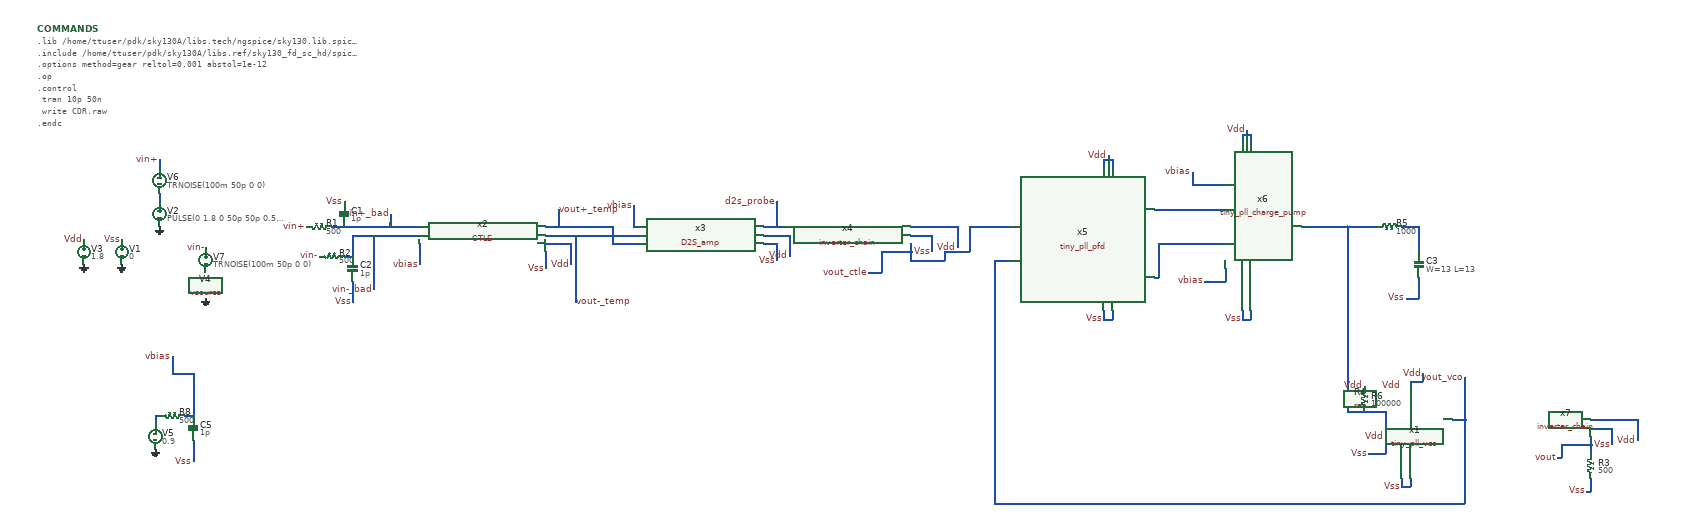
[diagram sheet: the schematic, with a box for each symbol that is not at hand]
v {xschem version=3.4.5 file_version=1.2
}
G {}
K {}
V {}
S {}
E {}
N 2080 490 2120 490 {
lab=Vss}
N 2120 470 2120 490 {
lab=Vss}
N 2030 390 2120 390 {
lab=#net1}
N 2120 390 2120 430 {
lab=#net1}
N 2180 320 2180 330 {
lab=Vdd}
N 2180 320 2210 320 {
lab=Vdd}
N 2210 300 2210 320 {
lab=Vdd}
N 2160 550 2160 570 {
lab=Vss}
N 2160 570 2180 570 {
lab=Vss}
N 2180 550 2180 570 {
lab=Vss}
N 120 -50 150 -50 {
lab=vout+_temp}
N 120 -30 150 -30 {
lab=vout-_temp}
N -390 -50 -360 -50 {
lab=vin+_bad}
N -360 -50 -290 -50 {
lab=vin+_bad}
N -360 20 -340 20 {
lab=vin-_bad}
N -290 -50 -180 -50 {
lab=vin+_bad}
N -340 80 -340 130 {
lab=Vss}
N -340 -30 -340 20 {
lab=vin-_bad}
N -340 -30 -180 -30 {
lab=vin-_bad}
N -180 -10 -180 0 {
lab=vbias}
N 120 -10 180 -10 {
lab=Vdd}
N 180 -10 180 40 {
lab=Vdd}
N 120 10 120 50 {
lab=Vss}
N -290 -30 -290 100 {
lab=vin-_bad}
N -250 -80 -250 -50 {
lab=vin+_bad}
N -800 -210 -800 -190 {
lab=vin+}
N -800 -130 -800 -110 {
lab=#net2}
N -180 0 -180 40 {
lab=vbias}
N 150 -90 150 -50 {
lab=vout+_temp}
N 190 -30 190 130 {
lab=vout-_temp}
N 150 -50 280 -50 {
lab=vout+_temp}
N -740 400 -720 400 {
lab=vbias}
N -720 460 -720 510 {
lab=Vss}
N -720 350 -720 400 {
lab=vbias}
N -720 300 -720 350 {
lab=vbias}
N -770 300 -720 300 {
lab=vbias}
N -770 260 -770 300 {
lab=vbias}
N -810 400 -800 400 {
lab=#net3}
N -810 400 -810 420 {
lab=#net3}
N 640 -50 690 -50 {
lab=d2s_probe}
N 1040 -50 1100 -50 {
lab=Vdd}
N 1100 -50 1100 0 {
lab=Vdd}
N 1040 -30 1040 10 {
lab=Vss}
N 990 -50 1040 -50 {
lab=Vdd}
N 990 -30 1040 -30 {
lab=Vss}
N 890 60 920 60 {
lab=vout_ctle}
N 920 20 920 60 {
lab=vout_ctle}
N 920 10 920 20 {
lab=vout_ctle}
N 920 10 990 10 {
lab=vout_ctle}
N 280 -10 340 -10 {
lab=vout+_temp}
N 280 -50 280 -10 {
lab=vout+_temp}
N 150 -30 340 -30 {
lab=vout-_temp}
N 330 -100 330 -50 {
lab=vbias}
N 330 -50 340 -50 {
lab=vbias}
N 640 -30 700 -30 {
lab=Vdd}
N 700 -30 700 20 {
lab=Vdd}
N 670 -10 670 30 {
lab=Vss}
N 640 -10 670 -10 {
lab=Vss}
N 670 -110 670 -50 {
lab=d2s_probe}
N 990 -10 990 10 {
lab=vout_ctle}
N 990 10 990 30 {
lab=vout_ctle}
N 1130 -50 1130 10 {
lab=vout_ctle}
N 1130 -50 1230 -50 {
lab=vout_ctle}
N 1070 10 1130 10 {
lab=vout_ctle}
N 1070 10 1070 30 {
lab=vout_ctle}
N 990 30 1070 30 {
lab=vout_ctle}
N 1570 -90 1740 -90 {
lab=#net4}
N 1580 -10 1740 -10 {
lab=#net5}
N 1580 -10 1580 70 {
lab=#net5}
N 1570 70 1580 70 {
lab=#net5}
N 2170 120 2200 120 {
lab=Vss}
N 2200 70 2200 120 {
lab=Vss}
N 2200 -50 2200 10 {
lab=#net6}
N 2030 -50 2030 390 {
lab=#net1}
N 2310 410 2310 610 {
lab=vout_vco}
N 1190 610 2310 610 {
lab=vout_vco}
N 1190 30 1190 610 {
lab=vout_vco}
N 1190 30 1230 30 {
lab=vout_vco}
N 1780 -270 1780 -250 {
lab=Vdd}
N 1780 -270 1800 -270 {
lab=Vdd}
N 1800 -270 1800 -250 {
lab=Vdd}
N 1790 -280 1790 -270 {
lab=Vdd}
N 1450 -210 1450 -190 {
lab=Vdd}
N 1450 -210 1470 -210 {
lab=Vdd}
N 1470 -210 1470 -190 {
lab=Vdd}
N 1460 -220 1460 -210 {
lab=Vdd}
N 1780 150 1780 170 {
lab=Vss}
N 1780 170 1800 170 {
lab=Vss}
N 1800 150 1800 170 {
lab=Vss}
N 1450 150 1450 170 {
lab=Vss}
N 1450 170 1470 170 {
lab=Vss}
N 1470 150 1470 170 {
lab=Vss}
N 1660 -180 1660 -150 {
lab=vbias}
N 1660 -150 1740 -150 {
lab=vbias}
N 1690 80 1740 80 {
lab=vbias}
N 1740 50 1740 80 {
lab=vbias}
N 2660 410 2720 410 {
lab=Vdd}
N 2720 410 2720 460 {
lab=Vdd}
N 2660 430 2660 470 {
lab=Vss}
N 2610 410 2660 410 {
lab=Vdd}
N 2610 430 2660 430 {
lab=Vss}
N 2540 470 2540 480 {
lab=vout}
N 2540 470 2610 470 {
lab=vout}
N 2610 450 2610 470 {
lab=vout}
N 2610 470 2610 490 {
lab=vout}
N 2540 480 2540 500 {
lab=vout}
N 2530 500 2540 500 {
lab=vout}
N 2600 580 2610 580 {
lab=Vss}
N 2610 550 2610 580 {
lab=Vss}
N 2280 410 2310 410 {
lab=vout_vco}
N 2310 310 2310 410 {
lab=vout_vco}
N 2160 -50 2200 -50 {
lab=#net6}
N 1920 -50 2030 -50 {
lab=#net1}
N 2030 -50 2100 -50 {
lab=#net1}
C {tiny_pll_vco.sym} 2200 430 0 0 {name=x1}
C {devices/lab_wire.sym} 2080 490 0 0 {name=p2 sig_type=std_logic lab=Vss
}
C {devices/lab_wire.sym} 2120 450 0 0 {name=p4 sig_type=std_logic lab=Vdd
}
C {devices/lab_wire.sym} 2160 330 0 0 {name=p3 sig_type=std_logic lab=Vdd
}
C {devices/lab_wire.sym} 2210 300 0 0 {name=p6 sig_type=std_logic lab=Vdd
}
C {devices/lab_wire.sym} 2160 570 0 0 {name=p8 sig_type=std_logic lab=Vss
}
C {devices/vsource.sym} -980 10 0 0 {name=V3 value=1.8 savecurrent=false}
C {devices/gnd.sym} -980 40 0 0 {name=l3 lab=GND}
C {devices/lab_wire.sym} -980 -20 0 0 {name=p5 sig_type=std_logic lab=Vdd
}
C {devices/vsource.sym} -890 10 0 0 {name=V1 value=0 savecurrent=false}
C {devices/gnd.sym} -890 40 0 0 {name=l1 lab=GND}
C {devices/lab_wire.sym} -890 -20 0 0 {name=p1 sig_type=std_logic lab=Vss
}
C {devices/res.sym} -420 -50 1 0 {name=R1
value=500
footprint=1206
device=resistor
m=1}
C {devices/res.sym} -390 20 1 0 {name=R2
value=500
footprint=1206
device=resistor
m=1}
C {devices/capa.sym} -360 -80 0 0 {name=C1
m=1
value=1p
footprint=1206
device="ceramic capacitor"}
C {devices/capa.sym} -340 50 0 0 {name=C2
m=1
value=1p
footprint=1206
device="ceramic capacitor"}
C {devices/lab_wire.sym} -360 -110 0 0 {name=p10 sig_type=std_logic lab=Vss
}
C {devices/lab_wire.sym} -340 130 0 0 {name=p11 sig_type=std_logic lab=Vss
}
C {devices/simulator_commands_shown.sym} -1090 -520 0 0 {name=COMMANDS
simulator=ngspice
only_toplevel=false 
value="
.lib /home/ttuser/pdk/sky130A/libs.tech/ngspice/sky130.lib.spice tt
.include /home/ttuser/pdk/sky130A/libs.ref/sky130_fd_sc_hd/spice/sky130_fd_sc_hd.spice
.options method=gear reltol=0.001 abstol=1e-12
.op
.control
  tran 10p 50n
  write CDR.raw
.endc
"}
C {devices/vsource.sym} -800 -80 0 0 {name=V2 value="PULSE(0 1.8 0 50p 50p 0.5n 1n)" savecurrent=false
lab=vin+}
C {devices/gnd.sym} -800 -50 0 0 {name=l2 lab=GND}
C {devices/lab_wire.sym} -800 -210 0 0 {name=p9 sig_type=std_logic lab=vin+
}
C {devices/vsource.sym} -690 90 0 0 {name=V4 value="PULSE(1.8 0 0 50p 50p 0.5n 1n)" savecurrent=false}
C {devices/gnd.sym} -690 120 0 0 {name=l4 lab=GND}
C {devices/lab_wire.sym} -690 0 0 0 {name=p12 sig_type=std_logic lab=vin-
}
C {devices/lab_wire.sym} -450 -50 0 0 {name=p13 sig_type=std_logic lab=vin+
}
C {devices/lab_wire.sym} -420 20 0 0 {name=p15 sig_type=std_logic lab=vin-
}
C {devices/vsource.sym} -810 450 0 0 {name=V5 value=0.9 savecurrent=false}
C {devices/gnd.sym} -810 480 0 0 {name=l5 lab=GND
value=vbias}
C {devices/lab_wire.sym} 180 40 0 0 {name=p16 sig_type=std_logic lab=Vdd
}
C {devices/lab_wire.sym} 120 50 0 0 {name=p18 sig_type=std_logic lab=Vss
}
C {devices/lab_wire.sym} -250 -80 0 0 {name=p19 sig_type=std_logic lab=vin+_bad
}
C {devices/lab_wire.sym} -290 100 0 0 {name=p20 sig_type=std_logic lab=vin-_bad
}
C {devices/vsource.sym} -800 -160 0 0 {name=V6 value="TRNOISE(100m 50p 0 0)" savecurrent=false
lab=vin+}
C {devices/vsource.sym} -690 30 0 0 {name=V7 value="TRNOISE(100m 50p 0 0)" savecurrent=false
lab=vin+}
C {CTLE.sym} -30 -20 0 0 {name=x2}
C {devices/lab_wire.sym} 150 -90 0 1 {name=p21 sig_type=std_logic lab=vout+_temp
}
C {devices/lab_wire.sym} 190 130 0 1 {name=p24 sig_type=std_logic lab=vout-_temp
}
C {devices/lab_wire.sym} -770 260 0 0 {name=p28 sig_type=std_logic lab=vbias
}
C {devices/res.sym} -770 400 1 0 {name=R8
value=500
footprint=1206
device=resistor
m=1}
C {devices/capa.sym} -720 430 0 0 {name=C5
m=1
value=1p
footprint=1206
device="ceramic capacitor"}
C {devices/lab_wire.sym} -720 510 0 0 {name=p29 sig_type=std_logic lab=Vss
}
C {devices/lab_wire.sym} -180 40 0 0 {name=p22 sig_type=std_logic lab=vbias
}
C {devices/lab_wire.sym} 1100 0 0 0 {name=p23 sig_type=std_logic lab=Vdd
}
C {devices/lab_wire.sym} 1040 10 0 0 {name=p25 sig_type=std_logic lab=Vss
}
C {devices/lab_wire.sym} 890 60 0 0 {name=p27 sig_type=std_logic lab=vout_ctle
}
C {D2S_amp.sym} 490 -30 0 0 {name=x3}
C {devices/lab_wire.sym} 330 -100 0 0 {name=p30 sig_type=std_logic lab=vbias
}
C {devices/lab_wire.sym} 700 20 0 0 {name=p31 sig_type=std_logic lab=Vdd
}
C {devices/lab_wire.sym} 670 30 0 0 {name=p32 sig_type=std_logic lab=Vss
}
C {devices/lab_wire.sym} 670 -110 0 0 {name=p33 sig_type=std_logic lab=d2s_probe
}
C {inverter_chain.sym} 840 -30 0 0 {name=x4}
C {tiny_pll_pfd.sym} 1370 -10 0 0 {name=x5}
C {tiny_pll_charge_pump.sym} 1840 -50 0 0 {name=x6}
C {sky130_fd_pr/cap_mim_m3_1.sym} 2200 40 0 0 {name=C3 model=cap_mim_m3_1 W=13 L=13 MF=1 spiceprefix=X}
C {devices/lab_wire.sym} 2170 120 0 0 {name=p26 sig_type=std_logic lab=Vss
}
C {devices/lab_wire.sym} 1790 -280 0 0 {name=p14 sig_type=std_logic lab=Vdd
}
C {devices/lab_wire.sym} 1460 -220 0 0 {name=p34 sig_type=std_logic lab=Vdd
}
C {devices/lab_wire.sym} 1780 170 0 0 {name=p35 sig_type=std_logic lab=Vss
}
C {devices/lab_wire.sym} 1450 170 0 0 {name=p36 sig_type=std_logic lab=Vss
}
C {devices/lab_wire.sym} 1660 -180 0 0 {name=p37 sig_type=std_logic lab=vbias
}
C {devices/lab_wire.sym} 1690 80 0 0 {name=p38 sig_type=std_logic lab=vbias
}
C {devices/lab_wire.sym} 2530 500 0 0 {name=p17 sig_type=std_logic lab=vout
}
C {devices/lab_wire.sym} 2720 460 0 0 {name=p7 sig_type=std_logic lab=Vdd
}
C {devices/lab_wire.sym} 2660 470 0 0 {name=p39 sig_type=std_logic lab=Vss
}
C {inverter_chain.sym} 2460 430 0 0 {name=x7}
C {devices/res.sym} 2610 520 0 1 {name=R3
value=500
footprint=1206
device=resistor
m=1}
C {devices/lab_wire.sym} 2600 580 0 0 {name=p40 sig_type=std_logic lab=Vss
}
C {devices/lab_wire.sym} 2310 310 0 0 {name=p41 sig_type=std_logic lab=vout_vco
}
C {devices/res.sym} 2060 360 0 1 {name=R4
value=100000
footprint=1206
device=resistor
m=1}
C {devices/lab_wire.sym} 2070 330 0 0 {name=p42 sig_type=std_logic lab=Vdd
}
C {devices/res.sym} 2130 -50 3 0 {name=R5
value=1000
footprint=1206
device=resistor
m=1}
C {devices/res.sym} 2070 360 0 1 {name=R6
value=100000
footprint=1206
device=resistor
m=1}
